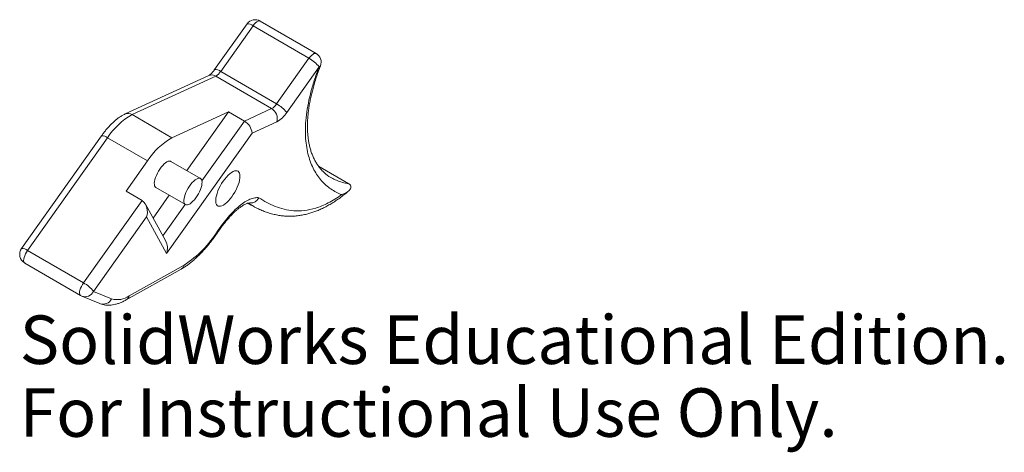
# Model space of a CAD drawing. Units: millimetres. Extents: x -32.1 to 66.1, y -42.2 to 0.9.
import ezdxf

# ---------------------------------------------------------------- set-up
doc = ezdxf.new("R2010")
doc.units = ezdxf.units.MM
doc.styles.add('SLDTEXTSTYLE0', font='TXT', dxfattribs={"width": 0.7})

msp = doc.modelspace()

# ---------------------------------------------------------------- linework, layer by layer
at = {"color": 7, "linetype": 'Continuous', "lineweight": 15}
for p, q in [((-9.409, 0.45), (-12.637, -4.096)), ((-8.808, 0.259), (-12.036, -4.286)), ((-3.237, -2.975), (-8.808, 0.259)), ((-2.52, -2.499), (-8.092, 0.736)), ((-6.465, -7.521), (-3.237, -2.975)), ((-2.226, -3.826), (-5.454, -8.371)), ((-13.219, -4.692), (-21.56, -8.519)), ((-12.526, -4.749), (-20.867, -8.576)), ((-6.955, -7.984), (-12.526, -4.749)), ((-12.036, -4.286), (-6.465, -7.521)), ((-20.867, -8.576), (-16.888, -10.887)), ((-11.261, -8.305), (-16.888, -10.887)), ((-15.415, -14.154), (-11.261, -8.305)), ((-11.261, -8.305), (-9.67, -9.229)), ((-9.67, -9.229), (-6.955, -7.984)), ((-13.902, -15.19), (-9.67, -9.229)), ((-6.434, -9.297), (-8.91, -10.433)), ((-23.917, -10.701), (-31.883, -21.917)), ((-8.91, -10.433), (-17.421, -22.419)), ((-23.317, -10.891), (-31.282, -22.108)), ((-23.317, -10.891), (-19.337, -13.201)), ((-19.337, -13.201), (-21.469, -16.204)), ((-14.045, -14.95), (-16.99, -13.24)), ((-2.293, -13.706), (0.737, -15.465)), ((-1.057, -14.842), (-1.025, -14.859)), ((-21.469, -16.204), (-19.877, -17.128)), ((-18.772, -18.882), (-17.159, -16.611)), ((-18.496, -15.835), (-15.551, -17.544)), ((-25.71, -25.342), (-19.877, -17.128)), ((-17.531, -21.131), (-19.542, -17.488)), ((-17.789, -20.663), (-15.568, -17.535)), ((-9.32, -17.407), (-9.008, -17.587)), ((-8.679, -17.768), (-9.296, -17.403)), ((-19.432, -18.776), (-24.7, -26.193)), ((-17.421, -22.419), (-19.432, -18.776)), ((-31.282, -22.108), (-25.71, -25.342)), ((-31.569, -23.361), (-25.998, -26.596)), ((-21.461, -27.041), (-15.985, -23.976)), ((-21.153, -26.631), (-15.677, -23.565)), ((-24.7, -26.193), (-22.914, -26.938)), ((-25.881, -26.654), (-24.095, -27.399))]:
    msp.add_line(p, q, dxfattribs=at)
at = {"color": 7, "linetype": 'Continuous', "lineweight": 15, "flags": 128}
for points in [[(-8.808, 0.259), (-8.686, 0.417), (-8.559, 0.551), (-8.433, 0.655), (-8.315, 0.724), (-8.209, 0.756), (-8.12, 0.748), (-8.092, 0.736)], [(-3.237, -2.975), (-3.114, -2.817), (-2.987, -2.683), (-2.861, -2.58), (-2.743, -2.51), (-2.637, -2.479), (-2.548, -2.486), (-2.52, -2.499)], [(-16.99, -13.24), (-17.04, -13.219), (-17.141, -13.208), (-17.258, -13.231), (-17.387, -13.289), (-17.526, -13.378), (-17.67, -13.498), (-17.816, -13.645), (-17.96, -13.814), (-18.099, -14.003), (-18.228, -14.205), (-18.345, -14.416), (-18.447, -14.63), (-18.53, -14.842), (-18.592, -15.046), (-18.633, -15.236), (-18.651, -15.409), (-18.645, -15.559), (-18.615, -15.682), (-18.564, -15.776), (-18.496, -15.835)], [(-12.453, -17.536), (-12.502, -17.413), (-12.527, -17.26), (-12.53, -17.082), (-12.508, -16.882), (-12.464, -16.664), (-12.397, -16.431), (-12.31, -16.189), (-12.203, -15.942), (-12.079, -15.695), (-11.94, -15.453), (-11.789, -15.221), (-11.629, -15.002), (-11.463, -14.802), (-11.295, -14.624), (-11.127, -14.472), (-10.962, -14.348), (-10.805, -14.255), (-10.657, -14.195), (-10.523, -14.17), (-10.404, -14.178), (-10.303, -14.221), (-10.222, -14.298), (-10.162, -14.406), (-10.124, -14.544), (-10.11, -14.71), (-10.12, -14.9), (-10.153, -15.109), (-10.209, -15.335), (-10.286, -15.573), (-10.383, -15.818), (-10.499, -16.066), (-10.631, -16.311), (-10.776, -16.549), (-10.932, -16.775), (-11.095, -16.985), (-11.263, -17.174), (-11.432, -17.34), (-11.598, -17.478), (-11.76, -17.587), (-11.912, -17.663), (-12.054, -17.706), (-12.181, -17.715), (-12.291, -17.689), (-12.382, -17.629), (-12.453, -17.536)], [(-13.949, -15.051), (-14.012, -14.973), (-14.095, -14.928), (-14.196, -14.917), (-14.313, -14.941), (-14.442, -14.998), (-14.581, -15.088), (-14.725, -15.208), (-14.871, -15.354), (-15.015, -15.524), (-15.154, -15.713), (-15.283, -15.915), (-15.4, -16.126), (-15.501, -16.34), (-15.585, -16.552), (-15.647, -16.755), (-15.688, -16.946), (-15.705, -17.118), (-15.7, -17.268), (-15.67, -17.392), (-15.619, -17.486), (-15.546, -17.547), (-15.453, -17.576), (-15.344, -17.569), (-15.22, -17.529), (-15.086, -17.455), (-14.944, -17.35), (-14.798, -17.216), (-14.653, -17.057), (-14.511, -16.878), (-14.376, -16.682), (-14.253, -16.474), (-14.143, -16.261), (-14.051, -16.048), (-13.978, -15.839), (-13.926, -15.641), (-13.897, -15.459), (-13.891, -15.298), (-13.908, -15.16), (-13.949, -15.051)], [(-12.318, -20.291), (-12.316, -20.289), (-12.317, -20.25), (-12.349, -20.191)], [(-31.569, -23.361), (-31.616, -23.321), (-31.656, -23.237), (-31.673, -23.121), (-31.663, -22.979), (-31.628, -22.817), (-31.57, -22.641), (-31.491, -22.459), (-31.393, -22.279), (-31.282, -22.108)], [(-25.998, -26.596), (-26.044, -26.555), (-26.085, -26.471), (-26.101, -26.356), (-26.091, -26.214), (-26.057, -26.051), (-25.998, -25.876), (-25.919, -25.694), (-25.821, -25.513), (-25.71, -25.342)]]:
    msp.add_lwpolyline(points, dxfattribs=at)
at = {"color": 7, "linetype": 'Continuous', "lineweight": 15}
for centre, radius, start, end in [((-8.594, -0.129), 1, 59.8637, 144.62034), ((-9.317, -0.301), 0.757, 47.81938, 97.03395), ((-3.022, -3.364), 1, 338.90932, 59.8637), ((-4.74, -5.786), 3.187, 37.94358, 61.86592), ((-2.252, -3.649), 0.179, 278.14077, 335.71056), ((-12.926, -5.372), 0.741, 57.30808, 113.23673), ((-12.545, -4.849), 0.759, 47.86396, 96.9325), ((-13.217, -3.528), 1.403, 299.48797, 327.27668), ((-7.645, -6.762), 1.403, 299.48797, 327.27668), ((-7.967, -10.331), 3.187, 37.94358, 61.86592), ((-17.371, -14.729), 7.077, 119.60921, 147.15544), ((-21.267, -9.199), 0.74, 57.3008, 113.45343), ((-7.558, -8.983), 1.167, 344.35942, 58.88404), ((-7.815, -6.854), 2.807, 299.48797, 327.27668), ((-10.401, -10.532), 1.494, 3.79797, 60.69856), ((-23.825, -11.452), 0.757, 47.81938, 97.03395), ((-13.391, -17.04), 7.077, 119.60921, 147.15544), ((-20.794, -18.259), 1.456, 339.21623, 50.97342), ((-21.629, -14.365), 10.958, 302.90127, 327.87967), ((-19.031, -21.907), 1.689, 342.36413, 27.35357), ((-31.067, -22.496), 1, 144.62034, 239.8637), ((-31.79, -22.668), 0.757, 47.81938, 97.03395), ((-16.315, -23.408), 0.657, 300.19729, 346.1312), ((-27.213, -28.153), 3.187, 37.94358, 61.86592), ((-25.546, -25.768), 0.947, 249.30502, 333.31849), ((-25.496, -25.731), 1, 239.8637, 247.3465), ((-23.761, -26.513), 0.947, 249.30502, 333.31849), ((-22.359, -24.926), 2.088, 254.56433, 305.2552), ((-21.791, -26.473), 0.657, 300.1698, 346.13194)]:
    msp.add_arc(centre, radius, start, end, dxfattribs=at)
for points, knots in [([(0.03, -16.551), (-0.36, -16.408), (-0.723, -16.218), (-1.394, -15.755), (-1.702, -15.481), (-2.263, -14.845), (-2.515, -14.483), (-2.844, -13.862), (-2.946, -13.642), (-3.129, -13.177), (-3.211, -12.931), (-3.352, -12.413), (-3.412, -12.139), (-3.507, -11.567), (-3.543, -11.268), (-3.586, -10.64), (-3.594, -10.312), (-3.581, -9.624), (-3.558, -9.262), (-3.442, -8.136), (-3.299, -7.341), (-2.979, -6.074), (-2.854, -5.64), (-2.566, -4.746), (-2.404, -4.288), (-2.226, -3.826)], [0, 0, 0, 0, 0.125, 0.125, 0.25, 0.25, 0.375, 0.375, 0.4375, 0.4375, 0.5, 0.5, 0.5625, 0.5625, 0.625, 0.625, 0.6875, 0.6875, 0.75, 0.75, 0.875, 0.875, 0.9375, 0.9375, 1, 1, 1, 1]), ([(-1.059, -14.852), (-1.141, -14.802), (-1.325, -14.692), (-1.591, -14.485), (-1.858, -14.238), (-2.106, -13.962), (-2.334, -13.661), (-2.545, -13.332), (-2.732, -12.984), (-2.896, -12.615), (-3.035, -12.234), (-3.149, -11.84), (-3.24, -11.435), (-3.308, -11.018), (-3.356, -10.588), (-3.383, -10.147), (-3.39, -9.692), (-3.377, -9.225), (-3.345, -8.746), (-3.293, -8.258), (-3.223, -7.763), (-3.135, -7.262), (-3.028, -6.752), (-2.903, -6.234), (-2.76, -5.706), (-2.599, -5.169), (-2.419, -4.624), (-2.249, -4.142), (-2.132, -3.84), (-2.087, -3.723)], [0, 0, 0, 0, 0.0409792, 0.0919958, 0.1424345, 0.1919183, 0.2403004, 0.2876149, 0.3347434, 0.3797883, 0.4226294, 0.4634896, 0.5026049, 0.5402006, 0.5764837, 0.611642, 0.6458453, 0.6792486, 0.7119944, 0.7441433, 0.7751879, 0.8055746, 0.8354661, 0.8650166, 0.8943748, 0.9236847, 0.9528778, 0.9817372, 1, 1, 1, 1]), ([(-12.637, -4.096), (-12.658, -4.124), (-12.718, -4.207), (-12.818, -4.332), (-12.932, -4.458), (-13.036, -4.559), (-13.12, -4.629), (-13.18, -4.671), (-13.211, -4.688), (-13.217, -4.691), (-13.219, -4.692)], [0, 0, 0, 0, 0.084097, 0.243652, 0.39991, 0.551163, 0.696229, 0.819898, 0.937829, 1, 1, 1, 1]), ([(-21.56, -8.519), (-21.611, -8.544), (-21.757, -8.614), (-21.996, -8.754), (-22.275, -8.947), (-22.551, -9.168), (-22.822, -9.413), (-23.086, -9.678), (-23.342, -9.961), (-23.591, -10.262), (-23.782, -10.511), (-23.888, -10.66), (-23.917, -10.701)], [0, 0, 0, 0, 0.061163, 0.175362, 0.290652, 0.405503, 0.51892, 0.630798, 0.741336, 0.850806, 0.959468, 1, 1, 1, 1]), ([(-0.991, -14.876), (-0.832, -14.964), (-0.489, -15.152), (0.087, -15.352), (0.52, -15.428), (0.737, -15.465)], [0, 0, 0, 0, 0.303877, 0.651953, 1, 1, 1, 1]), ([(0.737, -15.465), (0.791, -15.497), (0.834, -15.533), (0.894, -15.606), (0.914, -15.643), (0.948, -15.749), (0.943, -15.814), (0.896, -15.993), (0.818, -16.093), (0.635, -16.265), (0.527, -16.337), (0.293, -16.46), (0.166, -16.51), (0.03, -16.551)], [0, 0, 0, 0, 0.0625, 0.0625, 0.125, 0.125, 0.25, 0.25, 0.5, 0.5, 0.75, 0.75, 1, 1, 1, 1]), ([(-8.648, -17.784), (-8.596, -17.812), (-8.399, -17.919), (-8.047, -18.081), (-7.58, -18.269), (-7.099, -18.425), (-6.605, -18.55), (-6.132, -18.635), (-5.665, -18.687), (-5.205, -18.708), (-4.734, -18.695), (-4.268, -18.651), (-3.806, -18.576), (-3.364, -18.474), (-2.946, -18.351), (-2.537, -18.208), (-2.115, -18.034), (-1.681, -17.827), (-1.243, -17.591), (-0.811, -17.33), (-0.383, -17.046), (0.039, -16.738), (0.393, -16.463), (0.606, -16.28), (0.68, -16.217)], [0, 0, 0, 0, 0.022373, 0.085927, 0.146241, 0.21025, 0.271228, 0.329767, 0.379715, 0.432779, 0.483612, 0.532569, 0.579987, 0.626116, 0.665554, 0.704128, 0.744677, 0.786128, 0.826686, 0.86634, 0.905123, 0.943094, 0.980331, 1, 1, 1, 1]), ([(-8.231, -16.86), (-7.718, -17.199), (-7.181, -17.497), (-6.026, -17.949), (-5.412, -18.105), (-4.408, -18.173), (-4.058, -18.167), (-3.329, -18.085), (-2.95, -18.009), (-2.16, -17.768), (-1.746, -17.603), (-0.879, -17.161), (-0.433, -16.888), (0.03, -16.551)], [0, 0, 0, 0, 0.25, 0.25, 0.5, 0.5, 0.625, 0.625, 0.75, 0.75, 0.875, 0.875, 1, 1, 1, 1]), ([(-12.349, -20.191), (-12.005, -19.685), (-11.65, -19.215), (-11.098, -18.573), (-10.909, -18.369), (-10.536, -17.997), (-10.351, -17.828), (-9.984, -17.526), (-9.8, -17.393), (-9.447, -17.17), (-9.278, -17.081), (-8.952, -16.945), (-8.794, -16.898), (-8.573, -16.861), (-8.501, -16.854), (-8.363, -16.849), (-8.297, -16.854), (-8.231, -16.86)], [0, 0, 0, 0, 0.25, 0.25, 0.375, 0.375, 0.5, 0.5, 0.625, 0.625, 0.75, 0.75, 0.875, 0.875, 0.9375, 0.9375, 1, 1, 1, 1]), ([(-12.32, -20.289), (-12.263, -20.208), (-12.116, -19.997), (-11.883, -19.68), (-11.63, -19.351), (-11.386, -19.052), (-11.146, -18.777), (-10.904, -18.52), (-10.667, -18.288), (-10.435, -18.08), (-10.213, -17.898), (-10.005, -17.746), (-9.814, -17.623), (-9.645, -17.529), (-9.501, -17.463), (-9.389, -17.423), (-9.323, -17.406), (-9.261, -17.397), (-9.2, -17.392), (-9.138, -17.395), (-9.116, -17.396)], [0, 0, 0, 0, 0.045641, 0.117652, 0.182138, 0.24133, 0.303941, 0.364583, 0.425531, 0.486051, 0.545813, 0.604489, 0.661779, 0.717452, 0.77139, 0.823655, 0.864012, 0.90478, 0.966322, 1, 1, 1, 1]), ([(-9.116, -17.381), (-9.046, -17.384), (-8.871, -17.391), (-8.6, -17.273), (-8.377, -17.086), (-8.269, -16.93), (-8.233, -16.864), (-8.231, -16.86)], [0, 0, 0, 0, 0.202893, 0.500096, 0.798741, 0.987486, 1, 1, 1, 1]), ([(-15.985, -23.976), (-15.926, -23.942), (-15.755, -23.844), (-15.472, -23.659), (-15.135, -23.413), (-14.799, -23.141), (-14.467, -22.845), (-14.138, -22.527), (-13.813, -22.189), (-13.493, -21.831), (-13.179, -21.456), (-12.872, -21.065), (-12.584, -20.677), (-12.402, -20.414), (-12.318, -20.291)], [0, 0, 0, 0, 0.046633, 0.136886, 0.22665, 0.315792, 0.404269, 0.492123, 0.579434, 0.666286, 0.752759, 0.838927, 0.924855, 1, 1, 1, 1]), ([(-24.095, -27.399), (-24.035, -27.422), (-23.891, -27.478), (-23.653, -27.535), (-23.384, -27.568), (-23.105, -27.57), (-22.815, -27.541), (-22.514, -27.48), (-22.202, -27.386), (-21.879, -27.257), (-21.631, -27.135), (-21.491, -27.058), (-21.461, -27.041)], [0, 0, 0, 0, 0.072267, 0.1719091, 0.2729703, 0.3770131, 0.4851738, 0.5982971, 0.7166563, 0.8397029, 0.9661069, 1, 1, 1, 1])]:
    msp.add_open_spline(points, degree=3, knots=knots, dxfattribs=at)

# ---------------------------------------------------------------- texts
at = {"color": 7, "linetype": 'Continuous', "char_height": 4.83362, "attachment_point": 1, "style": 'SLDTEXTSTYLE0'}
for s, insert in [('SolidWorks Educational Edition.', (-32.067, -28.587)), ('For Instructional Use Only.', (-32.067, -35.838))]:
    msp.add_mtext(s, dxfattribs=dict(at, insert=insert))

doc.saveas('drawing.dxf')
